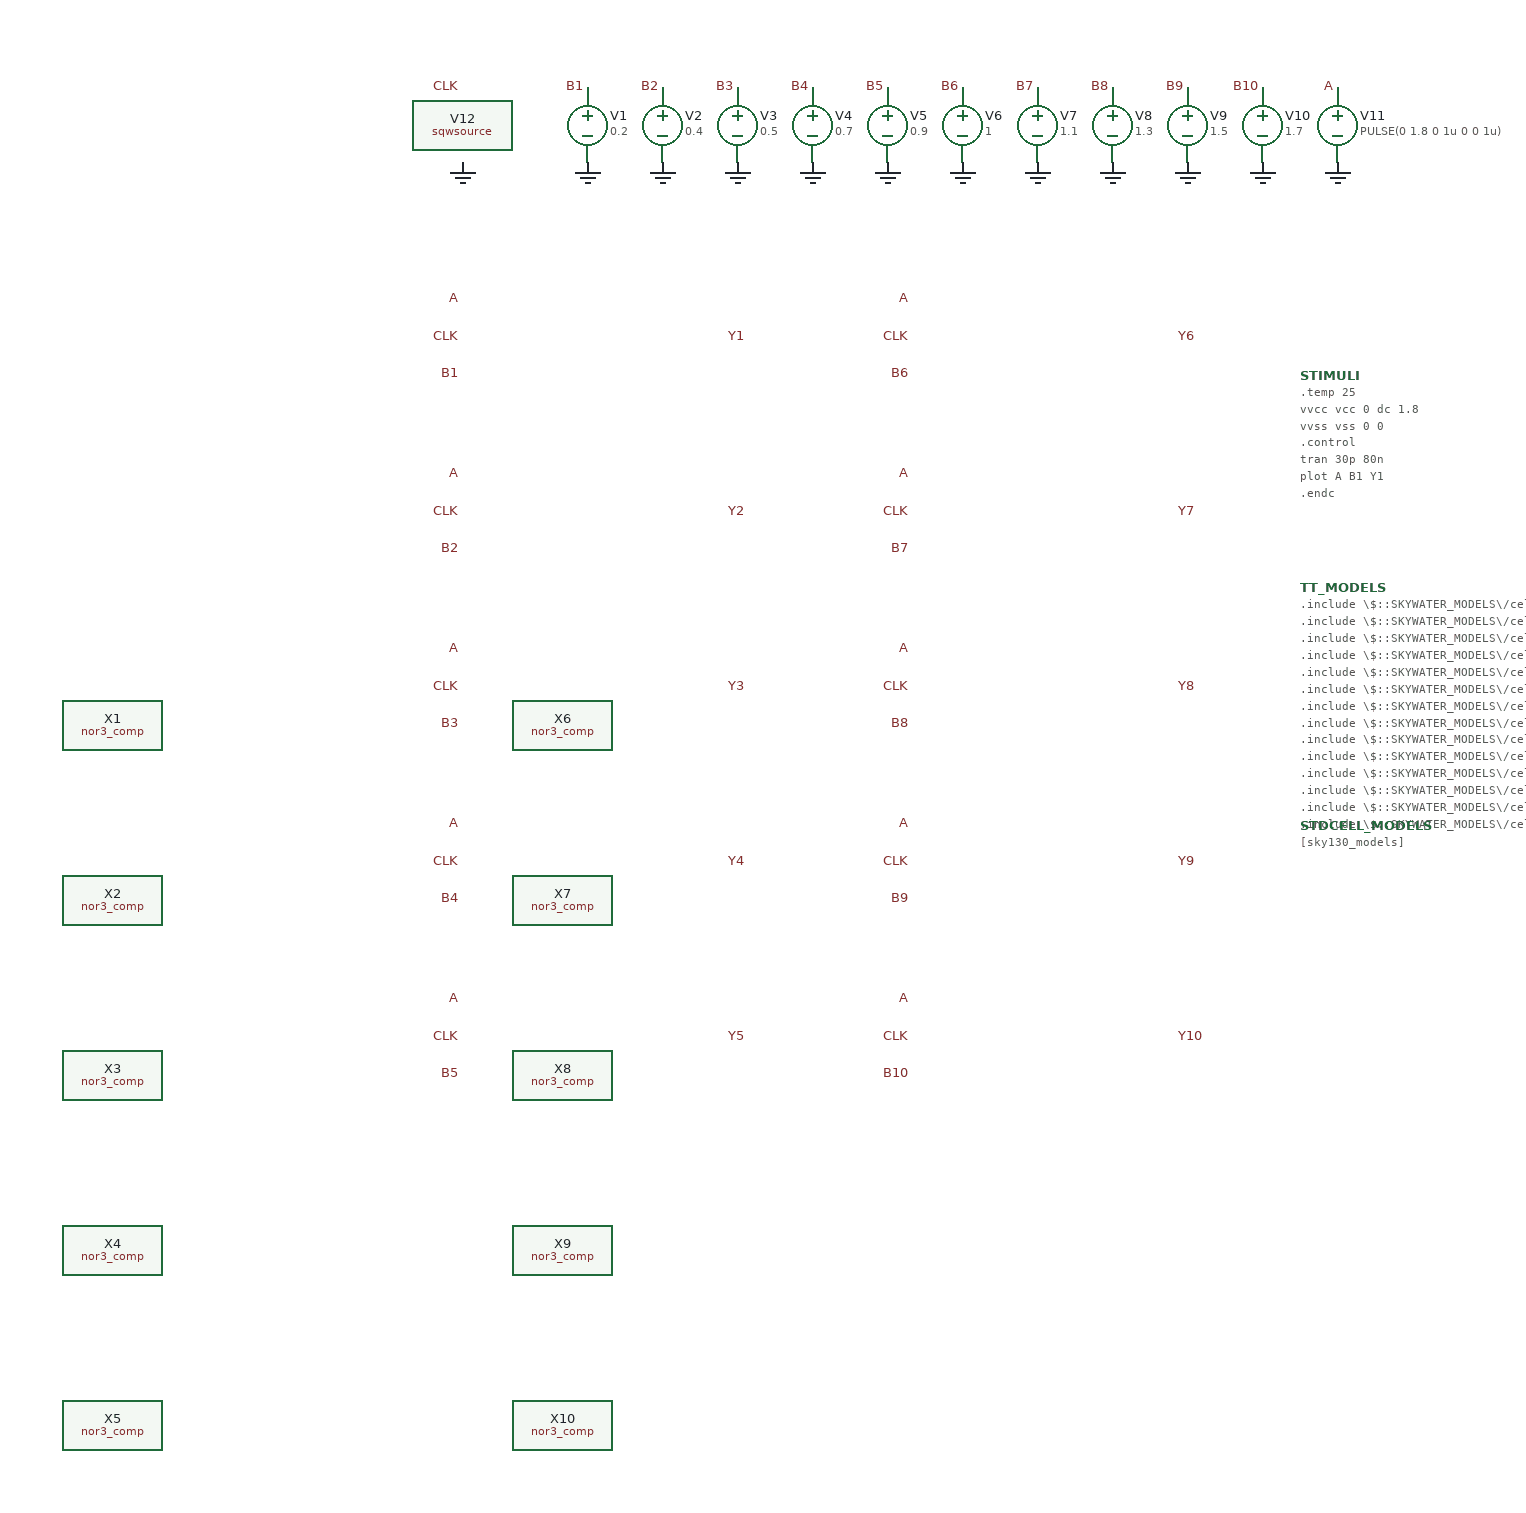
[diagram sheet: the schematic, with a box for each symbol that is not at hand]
v {xschem version=2.9.9 file_version=1.2 }
G {}
K {}
V {}
S {}
E {}
C {/home/ml2/projects/sky130_simulations/nor3_comp.sym} 400 -670 0 0 {name=X1}
C {/home/ml2/projects/sky130_simulations/nor3_comp.sym} 400 -530 0 0 {name=X2}
C {/home/ml2/projects/sky130_simulations/nor3_comp.sym} 400 -390 0 0 {name=X3}
C {/home/ml2/projects/sky130_simulations/nor3_comp.sym} 400 -250 0 0 {name=X4}
C {/home/ml2/projects/sky130_simulations/nor3_comp.sym} 400 -110 0 0 {name=X5}
C {/home/ml2/projects/sky130_simulations/nor3_comp.sym} 760 -670 0 0 {name=X6}
C {/home/ml2/projects/sky130_simulations/nor3_comp.sym} 760 -530 0 0 {name=X7}
C {/home/ml2/projects/sky130_simulations/nor3_comp.sym} 760 -390 0 0 {name=X8}
C {/home/ml2/projects/sky130_simulations/nor3_comp.sym} 760 -250 0 0 {name=X9}
C {/home/ml2/projects/sky130_simulations/nor3_comp.sym} 760 -110 0 0 {name=X10}
C {lab_pin.sym} 1250 -980 0 1 {name=l1 sig_type=std_logic lab=Y6}
C {lab_pin.sym} 1250 -840 0 1 {name=l2 sig_type=std_logic lab=Y7}
C {lab_pin.sym} 1250 -700 0 1 {name=l3 sig_type=std_logic lab=Y8}
C {lab_pin.sym} 1250 -560 0 1 {name=l4 sig_type=std_logic lab=Y9}
C {lab_pin.sym} 1250 -420 0 1 {name=l5 sig_type=std_logic lab=Y10}
C {lab_pin.sym} 890 -980 0 1 {name=l6 sig_type=std_logic lab=Y1}
C {lab_pin.sym} 890 -840 0 1 {name=l7 sig_type=std_logic lab=Y2}
C {lab_pin.sym} 890 -700 0 1 {name=l8 sig_type=std_logic lab=Y3}
C {lab_pin.sym} 890 -560 0 1 {name=l9 sig_type=std_logic lab=Y4}
C {lab_pin.sym} 890 -420 0 1 {name=l10 sig_type=std_logic lab=Y5}
C {lab_pin.sym} 680 -980 0 0 {name=l11 sig_type=std_logic lab=CLK}
C {lab_pin.sym} 680 -840 0 0 {name=l12 sig_type=std_logic lab=CLK}
C {lab_pin.sym} 680 -700 0 0 {name=l13 sig_type=std_logic lab=CLK}
C {lab_pin.sym} 680 -560 0 0 {name=l14 sig_type=std_logic lab=CLK}
C {lab_pin.sym} 680 -420 0 0 {name=l15 sig_type=std_logic lab=CLK}
C {lab_pin.sym} 1040 -980 0 0 {name=l16 sig_type=std_logic lab=CLK}
C {lab_pin.sym} 1040 -840 0 0 {name=l17 sig_type=std_logic lab=CLK}
C {lab_pin.sym} 1040 -700 0 0 {name=l18 sig_type=std_logic lab=CLK}
C {lab_pin.sym} 1040 -560 0 0 {name=l19 sig_type=std_logic lab=CLK}
C {lab_pin.sym} 1040 -420 0 0 {name=l20 sig_type=std_logic lab=CLK}
C {vsource.sym} 780 -1150 0 0 {name=V1 value=0.2}
C {gnd.sym} 680 -1120 0 0 {name=l21 lab=GND}
C {lab_pin.sym} 680 -1010 0 0 {name=l22 sig_type=std_logic lab=A}
C {lab_pin.sym} 680 -870 0 0 {name=l23 sig_type=std_logic lab=A}
C {lab_pin.sym} 680 -730 0 0 {name=l24 sig_type=std_logic lab=A}
C {lab_pin.sym} 680 -590 0 0 {name=l25 sig_type=std_logic lab=A}
C {lab_pin.sym} 680 -450 0 0 {name=l26 sig_type=std_logic lab=A}
C {lab_pin.sym} 1040 -450 0 0 {name=l27 sig_type=std_logic lab=A}
C {lab_pin.sym} 1040 -590 0 0 {name=l28 sig_type=std_logic lab=A}
C {lab_pin.sym} 1040 -730 0 0 {name=l29 sig_type=std_logic lab=A}
C {lab_pin.sym} 1040 -870 0 0 {name=l30 sig_type=std_logic lab=A}
C {lab_pin.sym} 1040 -1010 0 0 {name=l31 sig_type=std_logic lab=A}
C {lab_pin.sym} 680 -950 0 0 {name=l32 sig_type=std_logic lab=B1}
C {lab_pin.sym} 680 -810 0 0 {name=l33 sig_type=std_logic lab=B2}
C {lab_pin.sym} 680 -670 0 0 {name=l34 sig_type=std_logic lab=B3}
C {lab_pin.sym} 680 -530 0 0 {name=l35 sig_type=std_logic lab=B4}
C {lab_pin.sym} 680 -390 0 0 {name=l36 sig_type=std_logic lab=B5}
C {lab_pin.sym} 1040 -390 0 0 {name=l37 sig_type=std_logic lab=B10}
C {lab_pin.sym} 1040 -530 0 0 {name=l38 sig_type=std_logic lab=B9}
C {lab_pin.sym} 1040 -670 0 0 {name=l39 sig_type=std_logic lab=B8}
C {lab_pin.sym} 1040 -810 0 0 {name=l40 sig_type=std_logic lab=B7}
C {lab_pin.sym} 1040 -950 0 0 {name=l41 sig_type=std_logic lab=B6}
C {vsource.sym} 840 -1150 0 0 {name=V2 value=0.4}
C {vsource.sym} 900 -1150 0 0 {name=V3 value=0.5}
C {vsource.sym} 960 -1150 0 0 {name=V4 value=0.7}
C {vsource.sym} 1020 -1150 0 0 {name=V5 value=0.9}
C {vsource.sym} 1080 -1150 0 0 {name=V6 value=1}
C {vsource.sym} 1140 -1150 0 0 {name=V7 value=1.1}
C {vsource.sym} 1200 -1150 0 0 {name=V8 value=1.3}
C {vsource.sym} 1260 -1150 0 0 {name=V9 value=1.5}
C {vsource.sym} 1320 -1150 0 0 {name=V10 value=1.7}
C {vsource.sym} 1380 -1150 0 0 {name=V11 value="PULSE(0 1.8 0 1u 0 0 1u)"}
C {sqwsource.sym} 680 -1150 0 0 {name=V12 vhi=3 freq=50M}
C {gnd.sym} 780 -1120 0 0 {name=l42 lab=GND}
C {gnd.sym} 840 -1120 0 0 {name=l43 lab=GND}
C {gnd.sym} 900 -1120 0 0 {name=l44 lab=GND}
C {gnd.sym} 960 -1120 0 0 {name=l45 lab=GND}
C {gnd.sym} 1020 -1120 0 0 {name=l46 lab=GND}
C {gnd.sym} 1080 -1120 0 0 {name=l47 lab=GND}
C {gnd.sym} 1140 -1120 0 0 {name=l48 lab=GND}
C {gnd.sym} 1200 -1120 0 0 {name=l49 lab=GND}
C {gnd.sym} 1260 -1120 0 0 {name=l50 lab=GND}
C {gnd.sym} 1320 -1120 0 0 {name=l51 lab=GND}
C {gnd.sym} 1380 -1120 0 0 {name=l52 lab=GND}
C {lab_pin.sym} 1380 -1180 0 0 {name=l53 sig_type=std_logic lab=A}
C {lab_pin.sym} 1320 -1180 0 0 {name=l54 sig_type=std_logic lab=B10}
C {lab_pin.sym} 1260 -1180 0 0 {name=l55 sig_type=std_logic lab=B9}
C {lab_pin.sym} 1200 -1180 0 0 {name=l56 sig_type=std_logic lab=B8}
C {lab_pin.sym} 1140 -1180 0 0 {name=l57 sig_type=std_logic lab=B7}
C {lab_pin.sym} 1080 -1180 0 0 {name=l58 sig_type=std_logic lab=B6}
C {lab_pin.sym} 1020 -1180 0 0 {name=l59 sig_type=std_logic lab=B5}
C {lab_pin.sym} 960 -1180 0 0 {name=l60 sig_type=std_logic lab=B4}
C {lab_pin.sym} 900 -1180 0 0 {name=l61 sig_type=std_logic lab=B3}
C {lab_pin.sym} 840 -1180 0 0 {name=l62 sig_type=std_logic lab=B2}
C {lab_pin.sym} 780 -1180 0 0 {name=l63 sig_type=std_logic lab=B1}
C {lab_pin.sym} 680 -1180 0 0 {name=l64 sig_type=std_logic lab=CLK}
C {code.sym} 1350 -950 0 0 {name=STIMULI 
only_toplevel=true
value=" 
.temp 25
vvcc vcc 0 dc 1.8
vvss vss 0 0
.control
tran 30p 80n
plot A B1 Y1
.endc
"}
C {code.sym} 1350 -780 0 0 {name=TT_MODELS
only_toplevel=true
format="tcleval( @value )"
value="
.include \\\\$::SKYWATER_MODELS\\\\/cells/nfet_01v8/sky130_fd_pr__nfet_01v8__tt.corner.spice
.include \\\\$::SKYWATER_MODELS\\\\/cells/nfet_01v8_lvt/sky130_fd_pr__nfet_01v8_lvt__tt.corner.spice
.include \\\\$::SKYWATER_MODELS\\\\/cells/pfet_01v8/sky130_fd_pr__pfet_01v8__tt.corner.spice
.include \\\\$::SKYWATER_MODELS\\\\/cells/nfet_03v3_nvt/sky130_fd_pr__nfet_03v3_nvt__tt.corner.spice
.include \\\\$::SKYWATER_MODELS\\\\/cells/nfet_05v0_nvt/sky130_fd_pr__nfet_05v0_nvt__tt.corner.spice
.include \\\\$::SKYWATER_MODELS\\\\/cells/esd_nfet_01v8/sky130_fd_pr__esd_nfet_01v8__tt.corner.spice
.include \\\\$::SKYWATER_MODELS\\\\/cells/pfet_01v8_lvt/sky130_fd_pr__pfet_01v8_lvt__tt.corner.spice
.include \\\\$::SKYWATER_MODELS\\\\/cells/pfet_01v8_hvt/sky130_fd_pr__pfet_01v8_hvt__tt.corner.spice
.include \\\\$::SKYWATER_MODELS\\\\/cells/esd_pfet_g5v0d10v5/sky130_fd_pr__esd_pfet_g5v0d10v5__tt.corner.spice
.include \\\\$::SKYWATER_MODELS\\\\/cells/pfet_g5v0d10v5/sky130_fd_pr__pfet_g5v0d10v5__tt.corner.spice
.include \\\\$::SKYWATER_MODELS\\\\/cells/pfet_g5v0d16v0/sky130_fd_pr__pfet_g5v0d16v0__tt.corner.spice
.include \\\\$::SKYWATER_MODELS\\\\/cells/nfet_g5v0d10v5/sky130_fd_pr__nfet_g5v0d10v5__tt.corner.spice
.include \\\\$::SKYWATER_MODELS\\\\/cells/nfet_g5v0d16v0/sky130_fd_pr__nfet_g5v0d16v0__tt_discrete.corner.spice
.include \\\\$::SKYWATER_MODELS\\\\/cells/esd_nfet_g5v0d10v5/sky130_fd_pr__esd_nfet_g5v0d10v5__tt.corner.spice
.include \\\\$::SKYWATER_MODELS\\\\/models/corners/tt/nonfet.spice
* Mismatch parameters
.include \\\\$::SKYWATER_MODELS\\\\/cells/nfet_01v8/sky130_fd_pr__nfet_01v8__mismatch.corner.spice
.include \\\\$::SKYWATER_MODELS\\\\/cells/pfet_01v8/sky130_fd_pr__pfet_01v8__mismatch.corner.spice
.include \\\\$::SKYWATER_MODELS\\\\/cells/nfet_01v8_lvt/sky130_fd_pr__nfet_01v8_lvt__mismatch.corner.spice
.include \\\\$::SKYWATER_MODELS\\\\/cells/pfet_01v8_lvt/sky130_fd_pr__pfet_01v8_lvt__mismatch.corner.spice
.include \\\\$::SKYWATER_MODELS\\\\/cells/pfet_01v8_hvt/sky130_fd_pr__pfet_01v8_hvt__mismatch.corner.spice
.include \\\\$::SKYWATER_MODELS\\\\/cells/nfet_g5v0d10v5/sky130_fd_pr__nfet_g5v0d10v5__mismatch.corner.spice
.include \\\\$::SKYWATER_MODELS\\\\/cells/pfet_g5v0d10v5/sky130_fd_pr__pfet_g5v0d10v5__mismatch.corner.spice
.include \\\\$::SKYWATER_MODELS\\\\/cells/nfet_05v0_nvt/sky130_fd_pr__nfet_05v0_nvt__mismatch.corner.spice
.include \\\\$::SKYWATER_MODELS\\\\/cells/nfet_03v3_nvt/sky130_fd_pr__nfet_03v3_nvt__mismatch.corner.spice
* Resistor\\\\$::SKYWATER_MODELS\\\\/Capacitor
.include \\\\$::SKYWATER_MODELS\\\\/models/r+c/res_typical__cap_typical.spice
.include \\\\$::SKYWATER_MODELS\\\\/models/r+c/res_typical__cap_typical__lin.spice
* Special cells
.include \\\\$::SKYWATER_MODELS\\\\/models/corners/tt/specialized_cells.spice
* All models
.include \\\\$::SKYWATER_MODELS\\\\/models/all.spice
* Corner
.include \\\\$::SKYWATER_MODELS\\\\/models/corners/tt/rf.spice
"}
C {code.sym} 1350 -590 0 0 {name=STDCELL_MODELS 
only_toplevel=true
place=end
format="tcleval(@value )"
value="[sky130_models]"}
